# Copyright lowRISC contributors (OpenTitan project).
# Licensed under the Apache License, Version 2.0, see LICENSE for details.
# SPDX-License-Identifier: Apache-2.0
#
# This file was derived by lowRISC contributors (OpenTitan project) from the
# IHP Open PDK SRAM abstract RM_IHPSG13_1P_8192x32_c4.lef
# (https://github.com/IHP-GmbH/IHP-Open-PDK, ihp-sg13g2/libs.ref/sg13g2_sram/lef).
# It is a synthetic abstract, not an IHP release: the macro size and pins come
# from the Liberty view, the pin shapes, power straps and antenna values from
# the IHP abstract. IHP's original notice follows:
#
#   Copyright 2023 IHP PDK Authors
#
#   Licensed under the Apache License, Version 2.0 (the "License");
#   you may not use this file except in compliance with the License.
#   You may obtain a copy of the License at
#
#      https://www.apache.org/licenses/LICENSE-2.0
#
#   Unless required by applicable law or agreed to in writing, software
#   distributed under the License is distributed on an "AS IS" BASIS,
#   WITHOUT WARRANTIES OR CONDITIONS OF ANY KIND, either express or implied.
#   See the License for the specific language governing permissions and
#   limitations under the License.
#
#   Generated on Mon Apr  7 14:15:46 2025
#
# Generated by gen_synthetic_lef.py from the Liberty view. Do not edit.
# Synthetic abstract: no physical layout exists behind this macro.

VERSION 5.7 ;
BUSBITCHARS "[]" ;
DIVIDERCHAR "/" ;

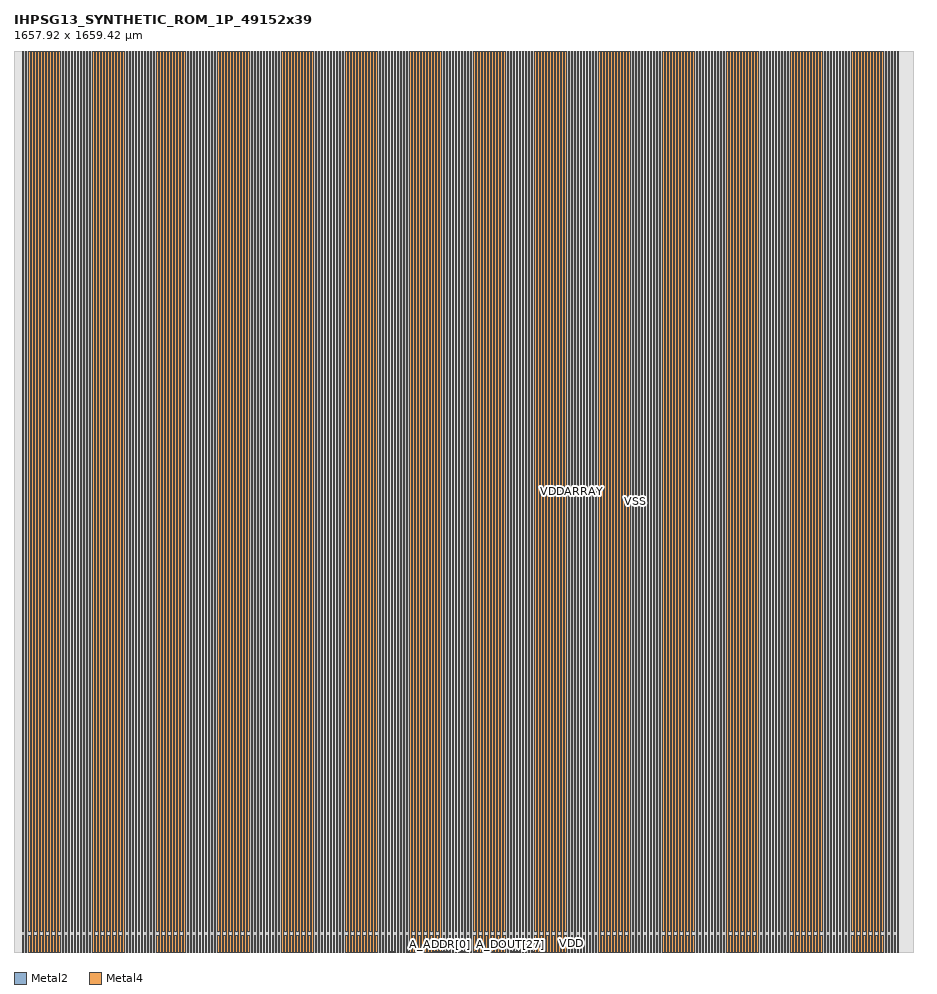
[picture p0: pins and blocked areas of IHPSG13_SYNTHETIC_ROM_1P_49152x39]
MACRO IHPSG13_SYNTHETIC_ROM_1P_49152x39
  CLASS BLOCK ;
  ORIGIN 0 0 ;
  FOREIGN IHPSG13_SYNTHETIC_ROM_1P_49152x39 0 0 ;
  SIZE 1657.92 BY 1659.42 ;
  SYMMETRY X Y R90 ;
  PIN A_DOUT[0]
    DIRECTION OUTPUT ;
    USE SIGNAL ;
    ANTENNADIFFAREA 0.988 LAYER Metal2 ;
    PORT
      LAYER Metal2 ;
        RECT 689.63 0 689.89 0.26 ;
    END
  END A_DOUT[0]
  PIN A_DOUT[1]
    DIRECTION OUTPUT ;
    USE SIGNAL ;
    ANTENNADIFFAREA 0.988 LAYER Metal2 ;
    PORT
      LAYER Metal2 ;
        RECT 694.43 0 694.69 0.26 ;
    END
  END A_DOUT[1]
  PIN A_DOUT[2]
    DIRECTION OUTPUT ;
    USE SIGNAL ;
    ANTENNADIFFAREA 0.988 LAYER Metal2 ;
    PORT
      LAYER Metal2 ;
        RECT 699.23 0 699.49 0.26 ;
    END
  END A_DOUT[2]
  PIN A_DOUT[3]
    DIRECTION OUTPUT ;
    USE SIGNAL ;
    ANTENNADIFFAREA 0.988 LAYER Metal2 ;
    PORT
      LAYER Metal2 ;
        RECT 704.03 0 704.29 0.26 ;
    END
  END A_DOUT[3]
  PIN A_DOUT[4]
    DIRECTION OUTPUT ;
    USE SIGNAL ;
    ANTENNADIFFAREA 0.988 LAYER Metal2 ;
    PORT
      LAYER Metal2 ;
        RECT 708.83 0 709.09 0.26 ;
    END
  END A_DOUT[4]
  PIN A_DOUT[5]
    DIRECTION OUTPUT ;
    USE SIGNAL ;
    ANTENNADIFFAREA 0.988 LAYER Metal2 ;
    PORT
      LAYER Metal2 ;
        RECT 713.63 0 713.89 0.26 ;
    END
  END A_DOUT[5]
  PIN A_DOUT[6]
    DIRECTION OUTPUT ;
    USE SIGNAL ;
    ANTENNADIFFAREA 0.988 LAYER Metal2 ;
    PORT
      LAYER Metal2 ;
        RECT 718.43 0 718.69 0.26 ;
    END
  END A_DOUT[6]
  PIN A_DOUT[7]
    DIRECTION OUTPUT ;
    USE SIGNAL ;
    ANTENNADIFFAREA 0.988 LAYER Metal2 ;
    PORT
      LAYER Metal2 ;
        RECT 723.23 0 723.49 0.26 ;
    END
  END A_DOUT[7]
  PIN A_DOUT[8]
    DIRECTION OUTPUT ;
    USE SIGNAL ;
    ANTENNADIFFAREA 0.988 LAYER Metal2 ;
    PORT
      LAYER Metal2 ;
        RECT 728.03 0 728.29 0.26 ;
    END
  END A_DOUT[8]
  PIN A_DOUT[9]
    DIRECTION OUTPUT ;
    USE SIGNAL ;
    ANTENNADIFFAREA 0.988 LAYER Metal2 ;
    PORT
      LAYER Metal2 ;
        RECT 732.83 0 733.09 0.26 ;
    END
  END A_DOUT[9]
  PIN A_DOUT[10]
    DIRECTION OUTPUT ;
    USE SIGNAL ;
    ANTENNADIFFAREA 0.988 LAYER Metal2 ;
    PORT
      LAYER Metal2 ;
        RECT 737.63 0 737.89 0.26 ;
    END
  END A_DOUT[10]
  PIN A_DOUT[11]
    DIRECTION OUTPUT ;
    USE SIGNAL ;
    ANTENNADIFFAREA 0.988 LAYER Metal2 ;
    PORT
      LAYER Metal2 ;
        RECT 742.43 0 742.69 0.26 ;
    END
  END A_DOUT[11]
  PIN A_DOUT[12]
    DIRECTION OUTPUT ;
    USE SIGNAL ;
    ANTENNADIFFAREA 0.988 LAYER Metal2 ;
    PORT
      LAYER Metal2 ;
        RECT 747.23 0 747.49 0.26 ;
    END
  END A_DOUT[12]
  PIN A_DOUT[13]
    DIRECTION OUTPUT ;
    USE SIGNAL ;
    ANTENNADIFFAREA 0.988 LAYER Metal2 ;
    PORT
      LAYER Metal2 ;
        RECT 752.03 0 752.29 0.26 ;
    END
  END A_DOUT[13]
  PIN A_DOUT[14]
    DIRECTION OUTPUT ;
    USE SIGNAL ;
    ANTENNADIFFAREA 0.988 LAYER Metal2 ;
    PORT
      LAYER Metal2 ;
        RECT 756.83 0 757.09 0.26 ;
    END
  END A_DOUT[14]
  PIN A_DOUT[15]
    DIRECTION OUTPUT ;
    USE SIGNAL ;
    ANTENNADIFFAREA 0.988 LAYER Metal2 ;
    PORT
      LAYER Metal2 ;
        RECT 761.63 0 761.89 0.26 ;
    END
  END A_DOUT[15]
  PIN A_DOUT[16]
    DIRECTION OUTPUT ;
    USE SIGNAL ;
    ANTENNADIFFAREA 0.988 LAYER Metal2 ;
    PORT
      LAYER Metal2 ;
        RECT 766.43 0 766.69 0.26 ;
    END
  END A_DOUT[16]
  PIN A_DOUT[17]
    DIRECTION OUTPUT ;
    USE SIGNAL ;
    ANTENNADIFFAREA 0.988 LAYER Metal2 ;
    PORT
      LAYER Metal2 ;
        RECT 771.23 0 771.49 0.26 ;
    END
  END A_DOUT[17]
  PIN A_DOUT[18]
    DIRECTION OUTPUT ;
    USE SIGNAL ;
    ANTENNADIFFAREA 0.988 LAYER Metal2 ;
    PORT
      LAYER Metal2 ;
        RECT 776.03 0 776.29 0.26 ;
    END
  END A_DOUT[18]
  PIN A_DLY
    DIRECTION INPUT ;
    USE SIGNAL ;
    ANTENNAMODEL OXIDE1 ;
      ANTENNAGATEAREA 0.20085 LAYER Metal2 ;
    PORT
      LAYER Metal2 ;
        RECT 780.83 0 781.09 0.26 ;
    END
  END A_DLY
  PIN A_ADDR[0]
    DIRECTION INPUT ;
    USE SIGNAL ;
    ANTENNAMODEL OXIDE1 ;
      ANTENNAGATEAREA 0.20085 LAYER Metal2 ;
    PORT
      LAYER Metal2 ;
        RECT 785.63 0 785.89 0.26 ;
    END
  END A_ADDR[0]
  PIN A_ADDR[1]
    DIRECTION INPUT ;
    USE SIGNAL ;
    ANTENNAMODEL OXIDE1 ;
      ANTENNAGATEAREA 0.20085 LAYER Metal2 ;
    PORT
      LAYER Metal2 ;
        RECT 790.43 0 790.69 0.26 ;
    END
  END A_ADDR[1]
  PIN A_ADDR[2]
    DIRECTION INPUT ;
    USE SIGNAL ;
    ANTENNAMODEL OXIDE1 ;
      ANTENNAGATEAREA 0.20085 LAYER Metal2 ;
    PORT
      LAYER Metal2 ;
        RECT 795.23 0 795.49 0.26 ;
    END
  END A_ADDR[2]
  PIN A_ADDR[3]
    DIRECTION INPUT ;
    USE SIGNAL ;
    ANTENNAMODEL OXIDE1 ;
      ANTENNAGATEAREA 0.20085 LAYER Metal2 ;
    PORT
      LAYER Metal2 ;
        RECT 800.03 0 800.29 0.26 ;
    END
  END A_ADDR[3]
  PIN A_ADDR[4]
    DIRECTION INPUT ;
    USE SIGNAL ;
    ANTENNAMODEL OXIDE1 ;
      ANTENNAGATEAREA 0.20085 LAYER Metal2 ;
    PORT
      LAYER Metal2 ;
        RECT 804.83 0 805.09 0.26 ;
    END
  END A_ADDR[4]
  PIN A_ADDR[5]
    DIRECTION INPUT ;
    USE SIGNAL ;
    ANTENNAMODEL OXIDE1 ;
      ANTENNAGATEAREA 0.20085 LAYER Metal2 ;
    PORT
      LAYER Metal2 ;
        RECT 809.63 0 809.89 0.26 ;
    END
  END A_ADDR[5]
  PIN A_ADDR[6]
    DIRECTION INPUT ;
    USE SIGNAL ;
    ANTENNAMODEL OXIDE1 ;
      ANTENNAGATEAREA 0.20085 LAYER Metal2 ;
    PORT
      LAYER Metal2 ;
        RECT 814.43 0 814.69 0.26 ;
    END
  END A_ADDR[6]
  PIN A_ADDR[7]
    DIRECTION INPUT ;
    USE SIGNAL ;
    ANTENNAMODEL OXIDE1 ;
      ANTENNAGATEAREA 0.20085 LAYER Metal2 ;
    PORT
      LAYER Metal2 ;
        RECT 819.23 0 819.49 0.26 ;
    END
  END A_ADDR[7]
  PIN A_ADDR[8]
    DIRECTION INPUT ;
    USE SIGNAL ;
    ANTENNAMODEL OXIDE1 ;
      ANTENNAGATEAREA 0.20085 LAYER Metal2 ;
    PORT
      LAYER Metal2 ;
        RECT 824.03 0 824.29 0.26 ;
    END
  END A_ADDR[8]
  PIN A_ADDR[9]
    DIRECTION INPUT ;
    USE SIGNAL ;
    ANTENNAMODEL OXIDE1 ;
      ANTENNAGATEAREA 0.20085 LAYER Metal2 ;
    PORT
      LAYER Metal2 ;
        RECT 828.83 0 829.09 0.26 ;
    END
  END A_ADDR[9]
  PIN A_ADDR[10]
    DIRECTION INPUT ;
    USE SIGNAL ;
    ANTENNAMODEL OXIDE1 ;
      ANTENNAGATEAREA 0.20085 LAYER Metal2 ;
    PORT
      LAYER Metal2 ;
        RECT 833.63 0 833.89 0.26 ;
    END
  END A_ADDR[10]
  PIN A_ADDR[11]
    DIRECTION INPUT ;
    USE SIGNAL ;
    ANTENNAMODEL OXIDE1 ;
      ANTENNAGATEAREA 0.20085 LAYER Metal2 ;
    PORT
      LAYER Metal2 ;
        RECT 838.43 0 838.69 0.26 ;
    END
  END A_ADDR[11]
  PIN A_ADDR[12]
    DIRECTION INPUT ;
    USE SIGNAL ;
    ANTENNAMODEL OXIDE1 ;
      ANTENNAGATEAREA 0.20085 LAYER Metal2 ;
    PORT
      LAYER Metal2 ;
        RECT 843.23 0 843.49 0.26 ;
    END
  END A_ADDR[12]
  PIN A_ADDR[13]
    DIRECTION INPUT ;
    USE SIGNAL ;
    ANTENNAMODEL OXIDE1 ;
      ANTENNAGATEAREA 0.20085 LAYER Metal2 ;
    PORT
      LAYER Metal2 ;
        RECT 848.03 0 848.29 0.26 ;
    END
  END A_ADDR[13]
  PIN A_ADDR[14]
    DIRECTION INPUT ;
    USE SIGNAL ;
    ANTENNAMODEL OXIDE1 ;
      ANTENNAGATEAREA 0.20085 LAYER Metal2 ;
    PORT
      LAYER Metal2 ;
        RECT 852.83 0 853.09 0.26 ;
    END
  END A_ADDR[14]
  PIN A_ADDR[15]
    DIRECTION INPUT ;
    USE SIGNAL ;
    ANTENNAMODEL OXIDE1 ;
      ANTENNAGATEAREA 0.20085 LAYER Metal2 ;
    PORT
      LAYER Metal2 ;
        RECT 857.63 0 857.89 0.26 ;
    END
  END A_ADDR[15]
  PIN A_REN
    DIRECTION INPUT ;
    USE SIGNAL ;
    ANTENNAMODEL OXIDE1 ;
      ANTENNAGATEAREA 0.20085 LAYER Metal2 ;
    PORT
      LAYER Metal2 ;
        RECT 862.43 0 862.69 0.26 ;
    END
  END A_REN
  PIN A_MEN
    DIRECTION INPUT ;
    USE SIGNAL ;
    ANTENNAMODEL OXIDE1 ;
      ANTENNAGATEAREA 0.20085 LAYER Metal2 ;
    PORT
      LAYER Metal2 ;
        RECT 867.23 0 867.49 0.26 ;
    END
  END A_MEN
  PIN A_CLK
    DIRECTION INPUT ;
    USE SIGNAL ;
    ANTENNAMODEL OXIDE1 ;
      ANTENNAGATEAREA 0.20085 LAYER Metal2 ;
    PORT
      LAYER Metal2 ;
        RECT 872.03 0 872.29 0.26 ;
    END
  END A_CLK
  PIN A_DOUT[19]
    DIRECTION OUTPUT ;
    USE SIGNAL ;
    ANTENNADIFFAREA 0.988 LAYER Metal2 ;
    PORT
      LAYER Metal2 ;
        RECT 876.83 0 877.09 0.26 ;
    END
  END A_DOUT[19]
  PIN A_DOUT[20]
    DIRECTION OUTPUT ;
    USE SIGNAL ;
    ANTENNADIFFAREA 0.988 LAYER Metal2 ;
    PORT
      LAYER Metal2 ;
        RECT 881.63 0 881.89 0.26 ;
    END
  END A_DOUT[20]
  PIN A_DOUT[21]
    DIRECTION OUTPUT ;
    USE SIGNAL ;
    ANTENNADIFFAREA 0.988 LAYER Metal2 ;
    PORT
      LAYER Metal2 ;
        RECT 886.43 0 886.69 0.26 ;
    END
  END A_DOUT[21]
  PIN A_DOUT[22]
    DIRECTION OUTPUT ;
    USE SIGNAL ;
    ANTENNADIFFAREA 0.988 LAYER Metal2 ;
    PORT
      LAYER Metal2 ;
        RECT 891.23 0 891.49 0.26 ;
    END
  END A_DOUT[22]
  PIN A_DOUT[23]
    DIRECTION OUTPUT ;
    USE SIGNAL ;
    ANTENNADIFFAREA 0.988 LAYER Metal2 ;
    PORT
      LAYER Metal2 ;
        RECT 896.03 0 896.29 0.26 ;
    END
  END A_DOUT[23]
  PIN A_DOUT[24]
    DIRECTION OUTPUT ;
    USE SIGNAL ;
    ANTENNADIFFAREA 0.988 LAYER Metal2 ;
    PORT
      LAYER Metal2 ;
        RECT 900.83 0 901.09 0.26 ;
    END
  END A_DOUT[24]
  PIN A_DOUT[25]
    DIRECTION OUTPUT ;
    USE SIGNAL ;
    ANTENNADIFFAREA 0.988 LAYER Metal2 ;
    PORT
      LAYER Metal2 ;
        RECT 905.63 0 905.89 0.26 ;
    END
  END A_DOUT[25]
  PIN A_DOUT[26]
    DIRECTION OUTPUT ;
    USE SIGNAL ;
    ANTENNADIFFAREA 0.988 LAYER Metal2 ;
    PORT
      LAYER Metal2 ;
        RECT 910.43 0 910.69 0.26 ;
    END
  END A_DOUT[26]
  PIN A_DOUT[27]
    DIRECTION OUTPUT ;
    USE SIGNAL ;
    ANTENNADIFFAREA 0.988 LAYER Metal2 ;
    PORT
      LAYER Metal2 ;
        RECT 915.23 0 915.49 0.26 ;
    END
  END A_DOUT[27]
  PIN A_DOUT[28]
    DIRECTION OUTPUT ;
    USE SIGNAL ;
    ANTENNADIFFAREA 0.988 LAYER Metal2 ;
    PORT
      LAYER Metal2 ;
        RECT 920.03 0 920.29 0.26 ;
    END
  END A_DOUT[28]
  PIN A_DOUT[29]
    DIRECTION OUTPUT ;
    USE SIGNAL ;
    ANTENNADIFFAREA 0.988 LAYER Metal2 ;
    PORT
      LAYER Metal2 ;
        RECT 924.83 0 925.09 0.26 ;
    END
  END A_DOUT[29]
  PIN A_DOUT[30]
    DIRECTION OUTPUT ;
    USE SIGNAL ;
    ANTENNADIFFAREA 0.988 LAYER Metal2 ;
    PORT
      LAYER Metal2 ;
        RECT 929.63 0 929.89 0.26 ;
    END
  END A_DOUT[30]
  PIN A_DOUT[31]
    DIRECTION OUTPUT ;
    USE SIGNAL ;
    ANTENNADIFFAREA 0.988 LAYER Metal2 ;
    PORT
      LAYER Metal2 ;
        RECT 934.43 0 934.69 0.26 ;
    END
  END A_DOUT[31]
  PIN A_DOUT[32]
    DIRECTION OUTPUT ;
    USE SIGNAL ;
    ANTENNADIFFAREA 0.988 LAYER Metal2 ;
    PORT
      LAYER Metal2 ;
        RECT 939.23 0 939.49 0.26 ;
    END
  END A_DOUT[32]
  PIN A_DOUT[33]
    DIRECTION OUTPUT ;
    USE SIGNAL ;
    ANTENNADIFFAREA 0.988 LAYER Metal2 ;
    PORT
      LAYER Metal2 ;
        RECT 944.03 0 944.29 0.26 ;
    END
  END A_DOUT[33]
  PIN A_DOUT[34]
    DIRECTION OUTPUT ;
    USE SIGNAL ;
    ANTENNADIFFAREA 0.988 LAYER Metal2 ;
    PORT
      LAYER Metal2 ;
        RECT 948.83 0 949.09 0.26 ;
    END
  END A_DOUT[34]
  PIN A_DOUT[35]
    DIRECTION OUTPUT ;
    USE SIGNAL ;
    ANTENNADIFFAREA 0.988 LAYER Metal2 ;
    PORT
      LAYER Metal2 ;
        RECT 953.63 0 953.89 0.26 ;
    END
  END A_DOUT[35]
  PIN A_DOUT[36]
    DIRECTION OUTPUT ;
    USE SIGNAL ;
    ANTENNADIFFAREA 0.988 LAYER Metal2 ;
    PORT
      LAYER Metal2 ;
        RECT 958.43 0 958.69 0.26 ;
    END
  END A_DOUT[36]
  PIN A_DOUT[37]
    DIRECTION OUTPUT ;
    USE SIGNAL ;
    ANTENNADIFFAREA 0.988 LAYER Metal2 ;
    PORT
      LAYER Metal2 ;
        RECT 963.23 0 963.49 0.26 ;
    END
  END A_DOUT[37]
  PIN A_DOUT[38]
    DIRECTION OUTPUT ;
    USE SIGNAL ;
    ANTENNADIFFAREA 0.988 LAYER Metal2 ;
    PORT
      LAYER Metal2 ;
        RECT 968.03 0 968.29 0.26 ;
    END
  END A_DOUT[38]
  PIN VDD
    DIRECTION INOUT ;
    USE POWER ;
    PORT
      LAYER Metal4 ;
        RECT 15.5 0 18.31 30.425 ;
    END
    PORT
      LAYER Metal4 ;
        RECT 26.74 0 29.55 30.425 ;
    END
    PORT
      LAYER Metal4 ;
        RECT 37.98 0 40.79 30.425 ;
    END
    PORT
      LAYER Metal4 ;
        RECT 49.22 0 52.03 30.425 ;
    END
    PORT
      LAYER Metal4 ;
        RECT 60.46 0 63.27 30.425 ;
    END
    PORT
      LAYER Metal4 ;
        RECT 71.7 0 74.51 30.425 ;
    END
    PORT
      LAYER Metal4 ;
        RECT 82.94 0 85.75 30.425 ;
    END
    PORT
      LAYER Metal4 ;
        RECT 94.18 0 96.99 30.425 ;
    END
    PORT
      LAYER Metal4 ;
        RECT 105.42 0 108.23 30.425 ;
    END
    PORT
      LAYER Metal4 ;
        RECT 116.66 0 119.47 30.425 ;
    END
    PORT
      LAYER Metal4 ;
        RECT 127.9 0 130.71 30.425 ;
    END
    PORT
      LAYER Metal4 ;
        RECT 139.14 0 141.95 30.425 ;
    END
    PORT
      LAYER Metal4 ;
        RECT 150.38 0 153.19 30.425 ;
    END
    PORT
      LAYER Metal4 ;
        RECT 161.62 0 164.43 30.425 ;
    END
    PORT
      LAYER Metal4 ;
        RECT 172.86 0 175.67 30.425 ;
    END
    PORT
      LAYER Metal4 ;
        RECT 184.1 0 186.91 30.425 ;
    END
    PORT
      LAYER Metal4 ;
        RECT 195.34 0 198.15 30.425 ;
    END
    PORT
      LAYER Metal4 ;
        RECT 206.58 0 209.39 30.425 ;
    END
    PORT
      LAYER Metal4 ;
        RECT 217.82 0 220.63 30.425 ;
    END
    PORT
      LAYER Metal4 ;
        RECT 229.06 0 231.87 30.425 ;
    END
    PORT
      LAYER Metal4 ;
        RECT 240.3 0 243.11 30.425 ;
    END
    PORT
      LAYER Metal4 ;
        RECT 251.54 0 254.35 30.425 ;
    END
    PORT
      LAYER Metal4 ;
        RECT 262.78 0 265.59 30.425 ;
    END
    PORT
      LAYER Metal4 ;
        RECT 274.02 0 276.83 30.425 ;
    END
    PORT
      LAYER Metal4 ;
        RECT 285.26 0 288.07 30.425 ;
    END
    PORT
      LAYER Metal4 ;
        RECT 296.5 0 299.31 30.425 ;
    END
    PORT
      LAYER Metal4 ;
        RECT 307.74 0 310.55 30.425 ;
    END
    PORT
      LAYER Metal4 ;
        RECT 318.98 0 321.79 30.425 ;
    END
    PORT
      LAYER Metal4 ;
        RECT 330.22 0 333.03 30.425 ;
    END
    PORT
      LAYER Metal4 ;
        RECT 341.46 0 344.27 30.425 ;
    END
    PORT
      LAYER Metal4 ;
        RECT 352.7 0 355.51 30.425 ;
    END
    PORT
      LAYER Metal4 ;
        RECT 363.94 0 366.75 30.425 ;
    END
    PORT
      LAYER Metal4 ;
        RECT 375.18 0 377.99 30.425 ;
    END
    PORT
      LAYER Metal4 ;
        RECT 386.42 0 389.23 30.425 ;
    END
    PORT
      LAYER Metal4 ;
        RECT 397.66 0 400.47 30.425 ;
    END
    PORT
      LAYER Metal4 ;
        RECT 408.9 0 411.71 30.425 ;
    END
    PORT
      LAYER Metal4 ;
        RECT 420.14 0 422.95 30.425 ;
    END
    PORT
      LAYER Metal4 ;
        RECT 431.38 0 434.19 30.425 ;
    END
    PORT
      LAYER Metal4 ;
        RECT 442.62 0 445.43 30.425 ;
    END
    PORT
      LAYER Metal4 ;
        RECT 453.86 0 456.67 30.425 ;
    END
    PORT
      LAYER Metal4 ;
        RECT 465.1 0 467.91 30.425 ;
    END
    PORT
      LAYER Metal4 ;
        RECT 476.34 0 479.15 30.425 ;
    END
    PORT
      LAYER Metal4 ;
        RECT 487.58 0 490.39 30.425 ;
    END
    PORT
      LAYER Metal4 ;
        RECT 498.82 0 501.63 30.425 ;
    END
    PORT
      LAYER Metal4 ;
        RECT 510.06 0 512.87 30.425 ;
    END
    PORT
      LAYER Metal4 ;
        RECT 521.3 0 524.11 30.425 ;
    END
    PORT
      LAYER Metal4 ;
        RECT 532.54 0 535.35 30.425 ;
    END
    PORT
      LAYER Metal4 ;
        RECT 543.78 0 546.59 30.425 ;
    END
    PORT
      LAYER Metal4 ;
        RECT 555.02 0 557.83 30.425 ;
    END
    PORT
      LAYER Metal4 ;
        RECT 566.26 0 569.07 30.425 ;
    END
    PORT
      LAYER Metal4 ;
        RECT 577.5 0 580.31 30.425 ;
    END
    PORT
      LAYER Metal4 ;
        RECT 588.74 0 591.55 30.425 ;
    END
    PORT
      LAYER Metal4 ;
        RECT 599.98 0 602.79 30.425 ;
    END
    PORT
      LAYER Metal4 ;
        RECT 611.22 0 614.03 30.425 ;
    END
    PORT
      LAYER Metal4 ;
        RECT 622.46 0 625.27 30.425 ;
    END
    PORT
      LAYER Metal4 ;
        RECT 633.7 0 636.51 30.425 ;
    END
    PORT
      LAYER Metal4 ;
        RECT 644.94 0 647.75 30.425 ;
    END
    PORT
      LAYER Metal4 ;
        RECT 656.18 0 658.99 30.425 ;
    END
    PORT
      LAYER Metal4 ;
        RECT 667.42 0 670.23 30.425 ;
    END
    PORT
      LAYER Metal4 ;
        RECT 678.66 0 681.47 30.425 ;
    END
    PORT
      LAYER Metal4 ;
        RECT 689.9 0 692.71 30.425 ;
    END
    PORT
      LAYER Metal4 ;
        RECT 701.14 0 703.95 30.425 ;
    END
    PORT
      LAYER Metal4 ;
        RECT 712.38 0 715.19 30.425 ;
    END
    PORT
      LAYER Metal4 ;
        RECT 723.62 0 726.43 30.425 ;
    END
    PORT
      LAYER Metal4 ;
        RECT 734.86 0 737.67 30.425 ;
    END
    PORT
      LAYER Metal4 ;
        RECT 746.1 0 748.91 30.425 ;
    END
    PORT
      LAYER Metal4 ;
        RECT 757.34 0 760.15 30.425 ;
    END
    PORT
      LAYER Metal4 ;
        RECT 768.58 0 771.39 30.425 ;
    END
    PORT
      LAYER Metal4 ;
        RECT 779.82 0 782.63 30.425 ;
    END
    PORT
      LAYER Metal4 ;
        RECT 791.06 0 793.87 30.425 ;
    END
    PORT
      LAYER Metal4 ;
        RECT 802.3 0 805.11 30.425 ;
    END
    PORT
      LAYER Metal4 ;
        RECT 813.54 0 816.35 30.425 ;
    END
    PORT
      LAYER Metal4 ;
        RECT 824.78 0 827.59 30.425 ;
    END
    PORT
      LAYER Metal4 ;
        RECT 836.02 0 838.83 30.425 ;
    END
    PORT
      LAYER Metal4 ;
        RECT 847.26 0 850.07 30.425 ;
    END
    PORT
      LAYER Metal4 ;
        RECT 858.5 0 861.31 30.425 ;
    END
    PORT
      LAYER Metal4 ;
        RECT 869.74 0 872.55 30.425 ;
    END
    PORT
      LAYER Metal4 ;
        RECT 880.98 0 883.79 30.425 ;
    END
    PORT
      LAYER Metal4 ;
        RECT 892.22 0 895.03 30.425 ;
    END
    PORT
      LAYER Metal4 ;
        RECT 903.46 0 906.27 30.425 ;
    END
    PORT
      LAYER Metal4 ;
        RECT 914.7 0 917.51 30.425 ;
    END
    PORT
      LAYER Metal4 ;
        RECT 925.94 0 928.75 30.425 ;
    END
    PORT
      LAYER Metal4 ;
        RECT 937.18 0 939.99 30.425 ;
    END
    PORT
      LAYER Metal4 ;
        RECT 948.42 0 951.23 30.425 ;
    END
    PORT
      LAYER Metal4 ;
        RECT 959.66 0 962.47 30.425 ;
    END
    PORT
      LAYER Metal4 ;
        RECT 970.9 0 973.71 30.425 ;
    END
    PORT
      LAYER Metal4 ;
        RECT 982.14 0 984.95 30.425 ;
    END
    PORT
      LAYER Metal4 ;
        RECT 993.38 0 996.19 30.425 ;
    END
    PORT
      LAYER Metal4 ;
        RECT 1004.62 0 1007.43 30.425 ;
    END
    PORT
      LAYER Metal4 ;
        RECT 1015.86 0 1018.67 30.425 ;
    END
    PORT
      LAYER Metal4 ;
        RECT 1027.1 0 1029.91 30.425 ;
    END
    PORT
      LAYER Metal4 ;
        RECT 1038.34 0 1041.15 30.425 ;
    END
    PORT
      LAYER Metal4 ;
        RECT 1049.58 0 1052.39 30.425 ;
    END
    PORT
      LAYER Metal4 ;
        RECT 1060.82 0 1063.63 30.425 ;
    END
    PORT
      LAYER Metal4 ;
        RECT 1072.06 0 1074.87 30.425 ;
    END
    PORT
      LAYER Metal4 ;
        RECT 1083.3 0 1086.11 30.425 ;
    END
    PORT
      LAYER Metal4 ;
        RECT 1094.54 0 1097.35 30.425 ;
    END
    PORT
      LAYER Metal4 ;
        RECT 1105.78 0 1108.59 30.425 ;
    END
    PORT
      LAYER Metal4 ;
        RECT 1117.02 0 1119.83 30.425 ;
    END
    PORT
      LAYER Metal4 ;
        RECT 1128.26 0 1131.07 30.425 ;
    END
    PORT
      LAYER Metal4 ;
        RECT 1139.5 0 1142.31 30.425 ;
    END
    PORT
      LAYER Metal4 ;
        RECT 1150.74 0 1153.55 30.425 ;
    END
    PORT
      LAYER Metal4 ;
        RECT 1161.98 0 1164.79 30.425 ;
    END
    PORT
      LAYER Metal4 ;
        RECT 1173.22 0 1176.03 30.425 ;
    END
    PORT
      LAYER Metal4 ;
        RECT 1184.46 0 1187.27 30.425 ;
    END
    PORT
      LAYER Metal4 ;
        RECT 1195.7 0 1198.51 30.425 ;
    END
    PORT
      LAYER Metal4 ;
        RECT 1206.94 0 1209.75 30.425 ;
    END
    PORT
      LAYER Metal4 ;
        RECT 1218.18 0 1220.99 30.425 ;
    END
    PORT
      LAYER Metal4 ;
        RECT 1229.42 0 1232.23 30.425 ;
    END
    PORT
      LAYER Metal4 ;
        RECT 1240.66 0 1243.47 30.425 ;
    END
    PORT
      LAYER Metal4 ;
        RECT 1251.9 0 1254.71 30.425 ;
    END
    PORT
      LAYER Metal4 ;
        RECT 1263.14 0 1265.95 30.425 ;
    END
    PORT
      LAYER Metal4 ;
        RECT 1274.38 0 1277.19 30.425 ;
    END
    PORT
      LAYER Metal4 ;
        RECT 1285.62 0 1288.43 30.425 ;
    END
    PORT
      LAYER Metal4 ;
        RECT 1296.86 0 1299.67 30.425 ;
    END
    PORT
      LAYER Metal4 ;
        RECT 1308.1 0 1310.91 30.425 ;
    END
    PORT
      LAYER Metal4 ;
        RECT 1319.34 0 1322.15 30.425 ;
    END
    PORT
      LAYER Metal4 ;
        RECT 1330.58 0 1333.39 30.425 ;
    END
    PORT
      LAYER Metal4 ;
        RECT 1341.82 0 1344.63 30.425 ;
    END
    PORT
      LAYER Metal4 ;
        RECT 1353.06 0 1355.87 30.425 ;
    END
    PORT
      LAYER Metal4 ;
        RECT 1364.3 0 1367.11 30.425 ;
    END
    PORT
      LAYER Metal4 ;
        RECT 1375.54 0 1378.35 30.425 ;
    END
    PORT
      LAYER Metal4 ;
        RECT 1386.78 0 1389.59 30.425 ;
    END
    PORT
      LAYER Metal4 ;
        RECT 1398.02 0 1400.83 30.425 ;
    END
    PORT
      LAYER Metal4 ;
        RECT 1409.26 0 1412.07 30.425 ;
    END
    PORT
      LAYER Metal4 ;
        RECT 1420.5 0 1423.31 30.425 ;
    END
    PORT
      LAYER Metal4 ;
        RECT 1431.74 0 1434.55 30.425 ;
    END
    PORT
      LAYER Metal4 ;
        RECT 1442.98 0 1445.79 30.425 ;
    END
    PORT
      LAYER Metal4 ;
        RECT 1454.22 0 1457.03 30.425 ;
    END
    PORT
      LAYER Metal4 ;
        RECT 1465.46 0 1468.27 30.425 ;
    END
    PORT
      LAYER Metal4 ;
        RECT 1476.7 0 1479.51 30.425 ;
    END
    PORT
      LAYER Metal4 ;
        RECT 1487.94 0 1490.75 30.425 ;
    END
    PORT
      LAYER Metal4 ;
        RECT 1499.18 0 1501.99 30.425 ;
    END
    PORT
      LAYER Metal4 ;
        RECT 1510.42 0 1513.23 30.425 ;
    END
    PORT
      LAYER Metal4 ;
        RECT 1521.66 0 1524.47 30.425 ;
    END
    PORT
      LAYER Metal4 ;
        RECT 1532.9 0 1535.71 30.425 ;
    END
    PORT
      LAYER Metal4 ;
        RECT 1544.14 0 1546.95 30.425 ;
    END
    PORT
      LAYER Metal4 ;
        RECT 1555.38 0 1558.19 30.425 ;
    END
    PORT
      LAYER Metal4 ;
        RECT 1566.62 0 1569.43 30.425 ;
    END
    PORT
      LAYER Metal4 ;
        RECT 1577.86 0 1580.67 30.425 ;
    END
    PORT
      LAYER Metal4 ;
        RECT 1589.1 0 1591.91 30.425 ;
    END
    PORT
      LAYER Metal4 ;
        RECT 1600.34 0 1603.15 30.425 ;
    END
    PORT
      LAYER Metal4 ;
        RECT 1611.58 0 1614.39 30.425 ;
    END
    PORT
      LAYER Metal4 ;
        RECT 1622.82 0 1625.63 30.425 ;
    END
  END VDD
  PIN VDDARRAY
    DIRECTION INOUT ;
    USE POWER ;
    PORT
      LAYER Metal4 ;
        RECT 15.5 37.065 18.31 1659.42 ;
    END
    PORT
      LAYER Metal4 ;
        RECT 26.74 37.065 29.55 1659.42 ;
    END
    PORT
      LAYER Metal4 ;
        RECT 37.98 37.065 40.79 1659.42 ;
    END
    PORT
      LAYER Metal4 ;
        RECT 49.22 37.065 52.03 1659.42 ;
    END
    PORT
      LAYER Metal4 ;
        RECT 60.46 37.065 63.27 1659.42 ;
    END
    PORT
      LAYER Metal4 ;
        RECT 71.7 37.065 74.51 1659.42 ;
    END
    PORT
      LAYER Metal4 ;
        RECT 82.94 37.065 85.75 1659.42 ;
    END
    PORT
      LAYER Metal4 ;
        RECT 94.18 37.065 96.99 1659.42 ;
    END
    PORT
      LAYER Metal4 ;
        RECT 105.42 37.065 108.23 1659.42 ;
    END
    PORT
      LAYER Metal4 ;
        RECT 116.66 37.065 119.47 1659.42 ;
    END
    PORT
      LAYER Metal4 ;
        RECT 127.9 37.065 130.71 1659.42 ;
    END
    PORT
      LAYER Metal4 ;
        RECT 139.14 37.065 141.95 1659.42 ;
    END
    PORT
      LAYER Metal4 ;
        RECT 150.38 37.065 153.19 1659.42 ;
    END
    PORT
      LAYER Metal4 ;
        RECT 161.62 37.065 164.43 1659.42 ;
    END
    PORT
      LAYER Metal4 ;
        RECT 172.86 37.065 175.67 1659.42 ;
    END
    PORT
      LAYER Metal4 ;
        RECT 184.1 37.065 186.91 1659.42 ;
    END
    PORT
      LAYER Metal4 ;
        RECT 195.34 37.065 198.15 1659.42 ;
    END
    PORT
      LAYER Metal4 ;
        RECT 206.58 37.065 209.39 1659.42 ;
    END
    PORT
      LAYER Metal4 ;
        RECT 217.82 37.065 220.63 1659.42 ;
    END
    PORT
      LAYER Metal4 ;
        RECT 229.06 37.065 231.87 1659.42 ;
    END
    PORT
      LAYER Metal4 ;
        RECT 240.3 37.065 243.11 1659.42 ;
    END
    PORT
      LAYER Metal4 ;
        RECT 251.54 37.065 254.35 1659.42 ;
    END
    PORT
      LAYER Metal4 ;
        RECT 262.78 37.065 265.59 1659.42 ;
    END
    PORT
      LAYER Metal4 ;
        RECT 274.02 37.065 276.83 1659.42 ;
    END
    PORT
      LAYER Metal4 ;
        RECT 285.26 37.065 288.07 1659.42 ;
    END
    PORT
      LAYER Metal4 ;
        RECT 296.5 37.065 299.31 1659.42 ;
    END
    PORT
      LAYER Metal4 ;
        RECT 307.74 37.065 310.55 1659.42 ;
    END
    PORT
      LAYER Metal4 ;
        RECT 318.98 37.065 321.79 1659.42 ;
    END
    PORT
      LAYER Metal4 ;
        RECT 330.22 37.065 333.03 1659.42 ;
    END
    PORT
      LAYER Metal4 ;
        RECT 341.46 37.065 344.27 1659.42 ;
    END
    PORT
      LAYER Metal4 ;
        RECT 352.7 37.065 355.51 1659.42 ;
    END
    PORT
      LAYER Metal4 ;
        RECT 363.94 37.065 366.75 1659.42 ;
    END
    PORT
      LAYER Metal4 ;
        RECT 375.18 37.065 377.99 1659.42 ;
    END
    PORT
      LAYER Metal4 ;
        RECT 386.42 37.065 389.23 1659.42 ;
    END
    PORT
      LAYER Metal4 ;
        RECT 397.66 37.065 400.47 1659.42 ;
    END
    PORT
      LAYER Metal4 ;
        RECT 408.9 37.065 411.71 1659.42 ;
    END
    PORT
      LAYER Metal4 ;
        RECT 420.14 37.065 422.95 1659.42 ;
    END
    PORT
      LAYER Metal4 ;
        RECT 431.38 37.065 434.19 1659.42 ;
    END
    PORT
      LAYER Metal4 ;
        RECT 442.62 37.065 445.43 1659.42 ;
    END
    PORT
      LAYER Metal4 ;
        RECT 453.86 37.065 456.67 1659.42 ;
    END
    PORT
      LAYER Metal4 ;
        RECT 465.1 37.065 467.91 1659.42 ;
    END
    PORT
      LAYER Metal4 ;
        RECT 476.34 37.065 479.15 1659.42 ;
    END
    PORT
      LAYER Metal4 ;
        RECT 487.58 37.065 490.39 1659.42 ;
    END
    PORT
      LAYER Metal4 ;
        RECT 498.82 37.065 501.63 1659.42 ;
    END
    PORT
      LAYER Metal4 ;
        RECT 510.06 37.065 512.87 1659.42 ;
    END
    PORT
      LAYER Metal4 ;
        RECT 521.3 37.065 524.11 1659.42 ;
    END
    PORT
      LAYER Metal4 ;
        RECT 532.54 37.065 535.35 1659.42 ;
    END
    PORT
      LAYER Metal4 ;
        RECT 543.78 37.065 546.59 1659.42 ;
    END
    PORT
      LAYER Metal4 ;
        RECT 555.02 37.065 557.83 1659.42 ;
    END
    PORT
      LAYER Metal4 ;
        RECT 566.26 37.065 569.07 1659.42 ;
    END
    PORT
      LAYER Metal4 ;
        RECT 577.5 37.065 580.31 1659.42 ;
    END
    PORT
      LAYER Metal4 ;
        RECT 588.74 37.065 591.55 1659.42 ;
    END
    PORT
      LAYER Metal4 ;
        RECT 599.98 37.065 602.79 1659.42 ;
    END
    PORT
      LAYER Metal4 ;
        RECT 611.22 37.065 614.03 1659.42 ;
    END
    PORT
      LAYER Metal4 ;
        RECT 622.46 37.065 625.27 1659.42 ;
    END
    PORT
      LAYER Metal4 ;
        RECT 633.7 37.065 636.51 1659.42 ;
    END
    PORT
      LAYER Metal4 ;
        RECT 644.94 37.065 647.75 1659.42 ;
    END
    PORT
      LAYER Metal4 ;
        RECT 656.18 37.065 658.99 1659.42 ;
    END
    PORT
      LAYER Metal4 ;
        RECT 667.42 37.065 670.23 1659.42 ;
    END
    PORT
      LAYER Metal4 ;
        RECT 678.66 37.065 681.47 1659.42 ;
    END
    PORT
      LAYER Metal4 ;
        RECT 689.9 37.065 692.71 1659.42 ;
    END
    PORT
      LAYER Metal4 ;
        RECT 701.14 37.065 703.95 1659.42 ;
    END
    PORT
      LAYER Metal4 ;
        RECT 712.38 37.065 715.19 1659.42 ;
    END
    PORT
      LAYER Metal4 ;
        RECT 723.62 37.065 726.43 1659.42 ;
    END
    PORT
      LAYER Metal4 ;
        RECT 734.86 37.065 737.67 1659.42 ;
    END
    PORT
      LAYER Metal4 ;
        RECT 746.1 37.065 748.91 1659.42 ;
    END
    PORT
      LAYER Metal4 ;
        RECT 757.34 37.065 760.15 1659.42 ;
    END
    PORT
      LAYER Metal4 ;
        RECT 768.58 37.065 771.39 1659.42 ;
    END
    PORT
      LAYER Metal4 ;
        RECT 779.82 37.065 782.63 1659.42 ;
    END
    PORT
      LAYER Metal4 ;
        RECT 791.06 37.065 793.87 1659.42 ;
    END
    PORT
      LAYER Metal4 ;
        RECT 802.3 37.065 805.11 1659.42 ;
    END
    PORT
      LAYER Metal4 ;
        RECT 813.54 37.065 816.35 1659.42 ;
    END
    PORT
      LAYER Metal4 ;
        RECT 824.78 37.065 827.59 1659.42 ;
    END
    PORT
      LAYER Metal4 ;
        RECT 836.02 37.065 838.83 1659.42 ;
    END
    PORT
      LAYER Metal4 ;
        RECT 847.26 37.065 850.07 1659.42 ;
    END
    PORT
      LAYER Metal4 ;
        RECT 858.5 37.065 861.31 1659.42 ;
    END
    PORT
      LAYER Metal4 ;
        RECT 869.74 37.065 872.55 1659.42 ;
    END
    PORT
      LAYER Metal4 ;
        RECT 880.98 37.065 883.79 1659.42 ;
    END
    PORT
      LAYER Metal4 ;
        RECT 892.22 37.065 895.03 1659.42 ;
    END
    PORT
      LAYER Metal4 ;
        RECT 903.46 37.065 906.27 1659.42 ;
    END
    PORT
      LAYER Metal4 ;
        RECT 914.7 37.065 917.51 1659.42 ;
    END
    PORT
      LAYER Metal4 ;
        RECT 925.94 37.065 928.75 1659.42 ;
    END
    PORT
      LAYER Metal4 ;
        RECT 937.18 37.065 939.99 1659.42 ;
    END
    PORT
      LAYER Metal4 ;
        RECT 948.42 37.065 951.23 1659.42 ;
    END
    PORT
      LAYER Metal4 ;
        RECT 959.66 37.065 962.47 1659.42 ;
    END
    PORT
      LAYER Metal4 ;
        RECT 970.9 37.065 973.71 1659.42 ;
    END
    PORT
      LAYER Metal4 ;
        RECT 982.14 37.065 984.95 1659.42 ;
    END
    PORT
      LAYER Metal4 ;
        RECT 993.38 37.065 996.19 1659.42 ;
    END
    PORT
      LAYER Metal4 ;
        RECT 1004.62 37.065 1007.43 1659.42 ;
    END
    PORT
      LAYER Metal4 ;
        RECT 1015.86 37.065 1018.67 1659.42 ;
    END
    PORT
      LAYER Metal4 ;
        RECT 1027.1 37.065 1029.91 1659.42 ;
    END
    PORT
      LAYER Metal4 ;
        RECT 1038.34 37.065 1041.15 1659.42 ;
    END
    PORT
      LAYER Metal4 ;
        RECT 1049.58 37.065 1052.39 1659.42 ;
    END
    PORT
      LAYER Metal4 ;
        RECT 1060.82 37.065 1063.63 1659.42 ;
    END
    PORT
      LAYER Metal4 ;
        RECT 1072.06 37.065 1074.87 1659.42 ;
    END
    PORT
      LAYER Metal4 ;
        RECT 1083.3 37.065 1086.11 1659.42 ;
    END
    PORT
      LAYER Metal4 ;
        RECT 1094.54 37.065 1097.35 1659.42 ;
    END
    PORT
      LAYER Metal4 ;
        RECT 1105.78 37.065 1108.59 1659.42 ;
    END
    PORT
      LAYER Metal4 ;
        RECT 1117.02 37.065 1119.83 1659.42 ;
    END
    PORT
      LAYER Metal4 ;
        RECT 1128.26 37.065 1131.07 1659.42 ;
    END
    PORT
      LAYER Metal4 ;
        RECT 1139.5 37.065 1142.31 1659.42 ;
    END
    PORT
      LAYER Metal4 ;
        RECT 1150.74 37.065 1153.55 1659.42 ;
    END
    PORT
      LAYER Metal4 ;
        RECT 1161.98 37.065 1164.79 1659.42 ;
    END
    PORT
      LAYER Metal4 ;
        RECT 1173.22 37.065 1176.03 1659.42 ;
    END
    PORT
      LAYER Metal4 ;
        RECT 1184.46 37.065 1187.27 1659.42 ;
    END
    PORT
      LAYER Metal4 ;
        RECT 1195.7 37.065 1198.51 1659.42 ;
    END
    PORT
      LAYER Metal4 ;
        RECT 1206.94 37.065 1209.75 1659.42 ;
    END
    PORT
      LAYER Metal4 ;
        RECT 1218.18 37.065 1220.99 1659.42 ;
    END
    PORT
      LAYER Metal4 ;
        RECT 1229.42 37.065 1232.23 1659.42 ;
    END
    PORT
      LAYER Metal4 ;
        RECT 1240.66 37.065 1243.47 1659.42 ;
    END
    PORT
      LAYER Metal4 ;
        RECT 1251.9 37.065 1254.71 1659.42 ;
    END
    PORT
      LAYER Metal4 ;
        RECT 1263.14 37.065 1265.95 1659.42 ;
    END
    PORT
      LAYER Metal4 ;
        RECT 1274.38 37.065 1277.19 1659.42 ;
    END
    PORT
      LAYER Metal4 ;
        RECT 1285.62 37.065 1288.43 1659.42 ;
    END
    PORT
      LAYER Metal4 ;
        RECT 1296.86 37.065 1299.67 1659.42 ;
    END
    PORT
      LAYER Metal4 ;
        RECT 1308.1 37.065 1310.91 1659.42 ;
    END
    PORT
      LAYER Metal4 ;
        RECT 1319.34 37.065 1322.15 1659.42 ;
    END
    PORT
      LAYER Metal4 ;
        RECT 1330.58 37.065 1333.39 1659.42 ;
    END
    PORT
      LAYER Metal4 ;
        RECT 1341.82 37.065 1344.63 1659.42 ;
    END
    PORT
      LAYER Metal4 ;
        RECT 1353.06 37.065 1355.87 1659.42 ;
    END
    PORT
      LAYER Metal4 ;
        RECT 1364.3 37.065 1367.11 1659.42 ;
    END
    PORT
      LAYER Metal4 ;
        RECT 1375.54 37.065 1378.35 1659.42 ;
    END
    PORT
      LAYER Metal4 ;
        RECT 1386.78 37.065 1389.59 1659.42 ;
    END
    PORT
      LAYER Metal4 ;
        RECT 1398.02 37.065 1400.83 1659.42 ;
    END
    PORT
      LAYER Metal4 ;
        RECT 1409.26 37.065 1412.07 1659.42 ;
    END
    PORT
      LAYER Metal4 ;
        RECT 1420.5 37.065 1423.31 1659.42 ;
    END
    PORT
      LAYER Metal4 ;
        RECT 1431.74 37.065 1434.55 1659.42 ;
    END
    PORT
      LAYER Metal4 ;
        RECT 1442.98 37.065 1445.79 1659.42 ;
    END
    PORT
      LAYER Metal4 ;
        RECT 1454.22 37.065 1457.03 1659.42 ;
    END
    PORT
      LAYER Metal4 ;
        RECT 1465.46 37.065 1468.27 1659.42 ;
    END
    PORT
      LAYER Metal4 ;
        RECT 1476.7 37.065 1479.51 1659.42 ;
    END
    PORT
      LAYER Metal4 ;
        RECT 1487.94 37.065 1490.75 1659.42 ;
    END
    PORT
      LAYER Metal4 ;
        RECT 1499.18 37.065 1501.99 1659.42 ;
    END
    PORT
      LAYER Metal4 ;
        RECT 1510.42 37.065 1513.23 1659.42 ;
    END
    PORT
      LAYER Metal4 ;
        RECT 1521.66 37.065 1524.47 1659.42 ;
    END
    PORT
      LAYER Metal4 ;
        RECT 1532.9 37.065 1535.71 1659.42 ;
    END
    PORT
      LAYER Metal4 ;
        RECT 1544.14 37.065 1546.95 1659.42 ;
    END
    PORT
      LAYER Metal4 ;
        RECT 1555.38 37.065 1558.19 1659.42 ;
    END
    PORT
      LAYER Metal4 ;
        RECT 1566.62 37.065 1569.43 1659.42 ;
    END
    PORT
      LAYER Metal4 ;
        RECT 1577.86 37.065 1580.67 1659.42 ;
    END
    PORT
      LAYER Metal4 ;
        RECT 1589.1 37.065 1591.91 1659.42 ;
    END
    PORT
      LAYER Metal4 ;
        RECT 1600.34 37.065 1603.15 1659.42 ;
    END
    PORT
      LAYER Metal4 ;
        RECT 1611.58 37.065 1614.39 1659.42 ;
    END
    PORT
      LAYER Metal4 ;
        RECT 1622.82 37.065 1625.63 1659.42 ;
    END
  END VDDARRAY
  PIN VSS
    DIRECTION INOUT ;
    USE GROUND ;
    PORT
      LAYER Metal4 ;
        RECT 21.12 0 23.93 1659.42 ;
    END
    PORT
      LAYER Metal4 ;
        RECT 32.36 0 35.17 1659.42 ;
    END
    PORT
      LAYER Metal4 ;
        RECT 43.6 0 46.41 1659.42 ;
    END
    PORT
      LAYER Metal4 ;
        RECT 54.84 0 57.65 1659.42 ;
    END
    PORT
      LAYER Metal4 ;
        RECT 66.08 0 68.89 1659.42 ;
    END
    PORT
      LAYER Metal4 ;
        RECT 77.32 0 80.13 1659.42 ;
    END
    PORT
      LAYER Metal4 ;
        RECT 88.56 0 91.37 1659.42 ;
    END
    PORT
      LAYER Metal4 ;
        RECT 99.8 0 102.61 1659.42 ;
    END
    PORT
      LAYER Metal4 ;
        RECT 111.04 0 113.85 1659.42 ;
    END
    PORT
      LAYER Metal4 ;
        RECT 122.28 0 125.09 1659.42 ;
    END
    PORT
      LAYER Metal4 ;
        RECT 133.52 0 136.33 1659.42 ;
    END
    PORT
      LAYER Metal4 ;
        RECT 144.76 0 147.57 1659.42 ;
    END
    PORT
      LAYER Metal4 ;
        RECT 156 0 158.81 1659.42 ;
    END
    PORT
      LAYER Metal4 ;
        RECT 167.24 0 170.05 1659.42 ;
    END
    PORT
      LAYER Metal4 ;
        RECT 178.48 0 181.29 1659.42 ;
    END
    PORT
      LAYER Metal4 ;
        RECT 189.72 0 192.53 1659.42 ;
    END
    PORT
      LAYER Metal4 ;
        RECT 200.96 0 203.77 1659.42 ;
    END
    PORT
      LAYER Metal4 ;
        RECT 212.2 0 215.01 1659.42 ;
    END
    PORT
      LAYER Metal4 ;
        RECT 223.44 0 226.25 1659.42 ;
    END
    PORT
      LAYER Metal4 ;
        RECT 234.68 0 237.49 1659.42 ;
    END
    PORT
      LAYER Metal4 ;
        RECT 245.92 0 248.73 1659.42 ;
    END
    PORT
      LAYER Metal4 ;
        RECT 257.16 0 259.97 1659.42 ;
    END
    PORT
      LAYER Metal4 ;
        RECT 268.4 0 271.21 1659.42 ;
    END
    PORT
      LAYER Metal4 ;
        RECT 279.64 0 282.45 1659.42 ;
    END
    PORT
      LAYER Metal4 ;
        RECT 290.88 0 293.69 1659.42 ;
    END
    PORT
      LAYER Metal4 ;
        RECT 302.12 0 304.93 1659.42 ;
    END
    PORT
      LAYER Metal4 ;
        RECT 313.36 0 316.17 1659.42 ;
    END
    PORT
      LAYER Metal4 ;
        RECT 324.6 0 327.41 1659.42 ;
    END
    PORT
      LAYER Metal4 ;
        RECT 335.84 0 338.65 1659.42 ;
    END
    PORT
      LAYER Metal4 ;
        RECT 347.08 0 349.89 1659.42 ;
    END
    PORT
      LAYER Metal4 ;
        RECT 358.32 0 361.13 1659.42 ;
    END
    PORT
      LAYER Metal4 ;
        RECT 369.56 0 372.37 1659.42 ;
    END
    PORT
      LAYER Metal4 ;
        RECT 380.8 0 383.61 1659.42 ;
    END
    PORT
      LAYER Metal4 ;
        RECT 392.04 0 394.85 1659.42 ;
    END
    PORT
      LAYER Metal4 ;
        RECT 403.28 0 406.09 1659.42 ;
    END
    PORT
      LAYER Metal4 ;
        RECT 414.52 0 417.33 1659.42 ;
    END
    PORT
      LAYER Metal4 ;
        RECT 425.76 0 428.57 1659.42 ;
    END
    PORT
      LAYER Metal4 ;
        RECT 437 0 439.81 1659.42 ;
    END
    PORT
      LAYER Metal4 ;
        RECT 448.24 0 451.05 1659.42 ;
    END
    PORT
      LAYER Metal4 ;
        RECT 459.48 0 462.29 1659.42 ;
    END
    PORT
      LAYER Metal4 ;
        RECT 470.72 0 473.53 1659.42 ;
    END
    PORT
      LAYER Metal4 ;
        RECT 481.96 0 484.77 1659.42 ;
    END
    PORT
      LAYER Metal4 ;
        RECT 493.2 0 496.01 1659.42 ;
    END
    PORT
      LAYER Metal4 ;
        RECT 504.44 0 507.25 1659.42 ;
    END
    PORT
      LAYER Metal4 ;
        RECT 515.68 0 518.49 1659.42 ;
    END
    PORT
      LAYER Metal4 ;
        RECT 526.92 0 529.73 1659.42 ;
    END
    PORT
      LAYER Metal4 ;
        RECT 538.16 0 540.97 1659.42 ;
    END
    PORT
      LAYER Metal4 ;
        RECT 549.4 0 552.21 1659.42 ;
    END
    PORT
      LAYER Metal4 ;
        RECT 560.64 0 563.45 1659.42 ;
    END
    PORT
      LAYER Metal4 ;
        RECT 571.88 0 574.69 1659.42 ;
    END
    PORT
      LAYER Metal4 ;
        RECT 583.12 0 585.93 1659.42 ;
    END
    PORT
      LAYER Metal4 ;
        RECT 594.36 0 597.17 1659.42 ;
    END
    PORT
      LAYER Metal4 ;
        RECT 605.6 0 608.41 1659.42 ;
    END
    PORT
      LAYER Metal4 ;
        RECT 616.84 0 619.65 1659.42 ;
    END
    PORT
      LAYER Metal4 ;
        RECT 628.08 0 630.89 1659.42 ;
    END
    PORT
      LAYER Metal4 ;
        RECT 639.32 0 642.13 1659.42 ;
    END
    PORT
      LAYER Metal4 ;
        RECT 650.56 0 653.37 1659.42 ;
    END
    PORT
      LAYER Metal4 ;
        RECT 661.8 0 664.61 1659.42 ;
    END
    PORT
      LAYER Metal4 ;
        RECT 673.04 0 675.85 1659.42 ;
    END
    PORT
      LAYER Metal4 ;
        RECT 684.28 0 687.09 1659.42 ;
    END
    PORT
      LAYER Metal4 ;
        RECT 695.52 0 698.33 1659.42 ;
    END
    PORT
      LAYER Metal4 ;
        RECT 706.76 0 709.57 1659.42 ;
    END
    PORT
      LAYER Metal4 ;
        RECT 718 0 720.81 1659.42 ;
    END
    PORT
      LAYER Metal4 ;
        RECT 729.24 0 732.05 1659.42 ;
    END
    PORT
      LAYER Metal4 ;
        RECT 740.48 0 743.29 1659.42 ;
    END
    PORT
      LAYER Metal4 ;
        RECT 751.72 0 754.53 1659.42 ;
    END
    PORT
      LAYER Metal4 ;
        RECT 762.96 0 765.77 1659.42 ;
    END
    PORT
      LAYER Metal4 ;
        RECT 774.2 0 777.01 1659.42 ;
    END
    PORT
      LAYER Metal4 ;
        RECT 785.44 0 788.25 1659.42 ;
    END
    PORT
      LAYER Metal4 ;
        RECT 796.68 0 799.49 1659.42 ;
    END
    PORT
      LAYER Metal4 ;
        RECT 807.92 0 810.73 1659.42 ;
    END
    PORT
      LAYER Metal4 ;
        RECT 819.16 0 821.97 1659.42 ;
    END
    PORT
      LAYER Metal4 ;
        RECT 830.4 0 833.21 1659.42 ;
    END
    PORT
      LAYER Metal4 ;
        RECT 841.64 0 844.45 1659.42 ;
    END
    PORT
      LAYER Metal4 ;
        RECT 852.88 0 855.69 1659.42 ;
    END
    PORT
      LAYER Metal4 ;
        RECT 864.12 0 866.93 1659.42 ;
    END
    PORT
      LAYER Metal4 ;
        RECT 875.36 0 878.17 1659.42 ;
    END
    PORT
      LAYER Metal4 ;
        RECT 886.6 0 889.41 1659.42 ;
    END
    PORT
      LAYER Metal4 ;
        RECT 897.84 0 900.65 1659.42 ;
    END
    PORT
      LAYER Metal4 ;
        RECT 909.08 0 911.89 1659.42 ;
    END
    PORT
      LAYER Metal4 ;
        RECT 920.32 0 923.13 1659.42 ;
    END
    PORT
      LAYER Metal4 ;
        RECT 931.56 0 934.37 1659.42 ;
    END
    PORT
      LAYER Metal4 ;
        RECT 942.8 0 945.61 1659.42 ;
    END
    PORT
      LAYER Metal4 ;
        RECT 954.04 0 956.85 1659.42 ;
    END
    PORT
      LAYER Metal4 ;
        RECT 965.28 0 968.09 1659.42 ;
    END
    PORT
      LAYER Metal4 ;
        RECT 976.52 0 979.33 1659.42 ;
    END
    PORT
      LAYER Metal4 ;
        RECT 987.76 0 990.57 1659.42 ;
    END
    PORT
      LAYER Metal4 ;
        RECT 999 0 1001.81 1659.42 ;
    END
    PORT
      LAYER Metal4 ;
        RECT 1010.24 0 1013.05 1659.42 ;
    END
    PORT
      LAYER Metal4 ;
        RECT 1021.48 0 1024.29 1659.42 ;
    END
    PORT
      LAYER Metal4 ;
        RECT 1032.72 0 1035.53 1659.42 ;
    END
    PORT
      LAYER Metal4 ;
        RECT 1043.96 0 1046.77 1659.42 ;
    END
    PORT
      LAYER Metal4 ;
        RECT 1055.2 0 1058.01 1659.42 ;
    END
    PORT
      LAYER Metal4 ;
        RECT 1066.44 0 1069.25 1659.42 ;
    END
    PORT
      LAYER Metal4 ;
        RECT 1077.68 0 1080.49 1659.42 ;
    END
    PORT
      LAYER Metal4 ;
        RECT 1088.92 0 1091.73 1659.42 ;
    END
    PORT
      LAYER Metal4 ;
        RECT 1100.16 0 1102.97 1659.42 ;
    END
    PORT
      LAYER Metal4 ;
        RECT 1111.4 0 1114.21 1659.42 ;
    END
    PORT
      LAYER Metal4 ;
        RECT 1122.64 0 1125.45 1659.42 ;
    END
    PORT
      LAYER Metal4 ;
        RECT 1133.88 0 1136.69 1659.42 ;
    END
    PORT
      LAYER Metal4 ;
        RECT 1145.12 0 1147.93 1659.42 ;
    END
    PORT
      LAYER Metal4 ;
        RECT 1156.36 0 1159.17 1659.42 ;
    END
    PORT
      LAYER Metal4 ;
        RECT 1167.6 0 1170.41 1659.42 ;
    END
    PORT
      LAYER Metal4 ;
        RECT 1178.84 0 1181.65 1659.42 ;
    END
    PORT
      LAYER Metal4 ;
        RECT 1190.08 0 1192.89 1659.42 ;
    END
    PORT
      LAYER Metal4 ;
        RECT 1201.32 0 1204.13 1659.42 ;
    END
    PORT
      LAYER Metal4 ;
        RECT 1212.56 0 1215.37 1659.42 ;
    END
    PORT
      LAYER Metal4 ;
        RECT 1223.8 0 1226.61 1659.42 ;
    END
    PORT
      LAYER Metal4 ;
        RECT 1235.04 0 1237.85 1659.42 ;
    END
    PORT
      LAYER Metal4 ;
        RECT 1246.28 0 1249.09 1659.42 ;
    END
    PORT
      LAYER Metal4 ;
        RECT 1257.52 0 1260.33 1659.42 ;
    END
    PORT
      LAYER Metal4 ;
        RECT 1268.76 0 1271.57 1659.42 ;
    END
    PORT
      LAYER Metal4 ;
        RECT 1280 0 1282.81 1659.42 ;
    END
    PORT
      LAYER Metal4 ;
        RECT 1291.24 0 1294.05 1659.42 ;
    END
    PORT
      LAYER Metal4 ;
        RECT 1302.48 0 1305.29 1659.42 ;
    END
    PORT
      LAYER Metal4 ;
        RECT 1313.72 0 1316.53 1659.42 ;
    END
    PORT
      LAYER Metal4 ;
        RECT 1324.96 0 1327.77 1659.42 ;
    END
    PORT
      LAYER Metal4 ;
        RECT 1336.2 0 1339.01 1659.42 ;
    END
    PORT
      LAYER Metal4 ;
        RECT 1347.44 0 1350.25 1659.42 ;
    END
    PORT
      LAYER Metal4 ;
        RECT 1358.68 0 1361.49 1659.42 ;
    END
    PORT
      LAYER Metal4 ;
        RECT 1369.92 0 1372.73 1659.42 ;
    END
    PORT
      LAYER Metal4 ;
        RECT 1381.16 0 1383.97 1659.42 ;
    END
    PORT
      LAYER Metal4 ;
        RECT 1392.4 0 1395.21 1659.42 ;
    END
    PORT
      LAYER Metal4 ;
        RECT 1403.64 0 1406.45 1659.42 ;
    END
    PORT
      LAYER Metal4 ;
        RECT 1414.88 0 1417.69 1659.42 ;
    END
    PORT
      LAYER Metal4 ;
        RECT 1426.12 0 1428.93 1659.42 ;
    END
    PORT
      LAYER Metal4 ;
        RECT 1437.36 0 1440.17 1659.42 ;
    END
    PORT
      LAYER Metal4 ;
        RECT 1448.6 0 1451.41 1659.42 ;
    END
    PORT
      LAYER Metal4 ;
        RECT 1459.84 0 1462.65 1659.42 ;
    END
    PORT
      LAYER Metal4 ;
        RECT 1471.08 0 1473.89 1659.42 ;
    END
    PORT
      LAYER Metal4 ;
        RECT 1482.32 0 1485.13 1659.42 ;
    END
    PORT
      LAYER Metal4 ;
        RECT 1493.56 0 1496.37 1659.42 ;
    END
    PORT
      LAYER Metal4 ;
        RECT 1504.8 0 1507.61 1659.42 ;
    END
    PORT
      LAYER Metal4 ;
        RECT 1516.04 0 1518.85 1659.42 ;
    END
    PORT
      LAYER Metal4 ;
        RECT 1527.28 0 1530.09 1659.42 ;
    END
    PORT
      LAYER Metal4 ;
        RECT 1538.52 0 1541.33 1659.42 ;
    END
    PORT
      LAYER Metal4 ;
        RECT 1549.76 0 1552.57 1659.42 ;
    END
    PORT
      LAYER Metal4 ;
        RECT 1561 0 1563.81 1659.42 ;
    END
    PORT
      LAYER Metal4 ;
        RECT 1572.24 0 1575.05 1659.42 ;
    END
    PORT
      LAYER Metal4 ;
        RECT 1583.48 0 1586.29 1659.42 ;
    END
    PORT
      LAYER Metal4 ;
        RECT 1594.72 0 1597.53 1659.42 ;
    END
    PORT
      LAYER Metal4 ;
        RECT 1605.96 0 1608.77 1659.42 ;
    END
    PORT
      LAYER Metal4 ;
        RECT 1617.2 0 1620.01 1659.42 ;
    END
    PORT
      LAYER Metal4 ;
        RECT 1628.44 0 1631.25 1659.42 ;
    END
  END VSS
  OBS
    LAYER Metal1 ;
      RECT 0 0 1657.92 1659.42 ;
    LAYER Metal2 ;
      RECT 0 1 1657.92 1659.42 ;
    LAYER Metal3 ;
      RECT 0 1 1657.92 1659.42 ;
    LAYER Metal4 ;
      RECT 0 0 15.2 1659.42 ;
      RECT 18.61 0 20.82 1659.42 ;
      RECT 24.23 0 26.44 1659.42 ;
      RECT 29.85 0 32.06 1659.42 ;
      RECT 35.47 0 37.68 1659.42 ;
      RECT 41.09 0 43.3 1659.42 ;
      RECT 46.71 0 48.92 1659.42 ;
      RECT 52.33 0 54.54 1659.42 ;
      RECT 57.95 0 60.16 1659.42 ;
      RECT 63.57 0 65.78 1659.42 ;
      RECT 69.19 0 71.4 1659.42 ;
      RECT 74.81 0 77.02 1659.42 ;
      RECT 80.43 0 82.64 1659.42 ;
      RECT 86.05 0 88.26 1659.42 ;
      RECT 91.67 0 93.88 1659.42 ;
      RECT 97.29 0 99.5 1659.42 ;
      RECT 102.91 0 105.12 1659.42 ;
      RECT 108.53 0 110.74 1659.42 ;
      RECT 114.15 0 116.36 1659.42 ;
      RECT 119.77 0 121.98 1659.42 ;
      RECT 125.39 0 127.6 1659.42 ;
      RECT 131.01 0 133.22 1659.42 ;
      RECT 136.63 0 138.84 1659.42 ;
      RECT 142.25 0 144.46 1659.42 ;
      RECT 147.87 0 150.08 1659.42 ;
      RECT 153.49 0 155.7 1659.42 ;
      RECT 159.11 0 161.32 1659.42 ;
      RECT 164.73 0 166.94 1659.42 ;
      RECT 170.35 0 172.56 1659.42 ;
      RECT 175.97 0 178.18 1659.42 ;
      RECT 181.59 0 183.8 1659.42 ;
      RECT 187.21 0 189.42 1659.42 ;
      RECT 192.83 0 195.04 1659.42 ;
      RECT 198.45 0 200.66 1659.42 ;
      RECT 204.07 0 206.28 1659.42 ;
      RECT 209.69 0 211.9 1659.42 ;
      RECT 215.31 0 217.52 1659.42 ;
      RECT 220.93 0 223.14 1659.42 ;
      RECT 226.55 0 228.76 1659.42 ;
      RECT 232.17 0 234.38 1659.42 ;
      RECT 237.79 0 240 1659.42 ;
      RECT 243.41 0 245.62 1659.42 ;
      RECT 249.03 0 251.24 1659.42 ;
      RECT 254.65 0 256.86 1659.42 ;
      RECT 260.27 0 262.48 1659.42 ;
      RECT 265.89 0 268.1 1659.42 ;
      RECT 271.51 0 273.72 1659.42 ;
      RECT 277.13 0 279.34 1659.42 ;
      RECT 282.75 0 284.96 1659.42 ;
      RECT 288.37 0 290.58 1659.42 ;
      RECT 293.99 0 296.2 1659.42 ;
      RECT 299.61 0 301.82 1659.42 ;
      RECT 305.23 0 307.44 1659.42 ;
      RECT 310.85 0 313.06 1659.42 ;
      RECT 316.47 0 318.68 1659.42 ;
      RECT 322.09 0 324.3 1659.42 ;
      RECT 327.71 0 329.92 1659.42 ;
      RECT 333.33 0 335.54 1659.42 ;
      RECT 338.95 0 341.16 1659.42 ;
      RECT 344.57 0 346.78 1659.42 ;
      RECT 350.19 0 352.4 1659.42 ;
      RECT 355.81 0 358.02 1659.42 ;
      RECT 361.43 0 363.64 1659.42 ;
      RECT 367.05 0 369.26 1659.42 ;
      RECT 372.67 0 374.88 1659.42 ;
      RECT 378.29 0 380.5 1659.42 ;
      RECT 383.91 0 386.12 1659.42 ;
      RECT 389.53 0 391.74 1659.42 ;
      RECT 395.15 0 397.36 1659.42 ;
      RECT 400.77 0 402.98 1659.42 ;
      RECT 406.39 0 408.6 1659.42 ;
      RECT 412.01 0 414.22 1659.42 ;
      RECT 417.63 0 419.84 1659.42 ;
      RECT 423.25 0 425.46 1659.42 ;
      RECT 428.87 0 431.08 1659.42 ;
      RECT 434.49 0 436.7 1659.42 ;
      RECT 440.11 0 442.32 1659.42 ;
      RECT 445.73 0 447.94 1659.42 ;
      RECT 451.35 0 453.56 1659.42 ;
      RECT 456.97 0 459.18 1659.42 ;
      RECT 462.59 0 464.8 1659.42 ;
      RECT 468.21 0 470.42 1659.42 ;
      RECT 473.83 0 476.04 1659.42 ;
      RECT 479.45 0 481.66 1659.42 ;
      RECT 485.07 0 487.28 1659.42 ;
      RECT 490.69 0 492.9 1659.42 ;
      RECT 496.31 0 498.52 1659.42 ;
      RECT 501.93 0 504.14 1659.42 ;
      RECT 507.55 0 509.76 1659.42 ;
      RECT 513.17 0 515.38 1659.42 ;
      RECT 518.79 0 521 1659.42 ;
      RECT 524.41 0 526.62 1659.42 ;
      RECT 530.03 0 532.24 1659.42 ;
      RECT 535.65 0 537.86 1659.42 ;
      RECT 541.27 0 543.48 1659.42 ;
      RECT 546.89 0 549.1 1659.42 ;
      RECT 552.51 0 554.72 1659.42 ;
      RECT 558.13 0 560.34 1659.42 ;
      RECT 563.75 0 565.96 1659.42 ;
      RECT 569.37 0 571.58 1659.42 ;
      RECT 574.99 0 577.2 1659.42 ;
      RECT 580.61 0 582.82 1659.42 ;
      RECT 586.23 0 588.44 1659.42 ;
      RECT 591.85 0 594.06 1659.42 ;
      RECT 597.47 0 599.68 1659.42 ;
      RECT 603.09 0 605.3 1659.42 ;
      RECT 608.71 0 610.92 1659.42 ;
      RECT 614.33 0 616.54 1659.42 ;
      RECT 619.95 0 622.16 1659.42 ;
      RECT 625.57 0 627.78 1659.42 ;
      RECT 631.19 0 633.4 1659.42 ;
      RECT 636.81 0 639.02 1659.42 ;
      RECT 642.43 0 644.64 1659.42 ;
      RECT 648.05 0 650.26 1659.42 ;
      RECT 653.67 0 655.88 1659.42 ;
      RECT 659.29 0 661.5 1659.42 ;
      RECT 664.91 0 667.12 1659.42 ;
      RECT 670.53 0 672.74 1659.42 ;
      RECT 676.15 0 678.36 1659.42 ;
      RECT 681.77 0 683.98 1659.42 ;
      RECT 687.39 0 689.6 1659.42 ;
      RECT 693.01 0 695.22 1659.42 ;
      RECT 698.63 0 700.84 1659.42 ;
      RECT 704.25 0 706.46 1659.42 ;
      RECT 709.87 0 712.08 1659.42 ;
      RECT 715.49 0 717.7 1659.42 ;
      RECT 721.11 0 723.32 1659.42 ;
      RECT 726.73 0 728.94 1659.42 ;
      RECT 732.35 0 734.56 1659.42 ;
      RECT 737.97 0 740.18 1659.42 ;
      RECT 743.59 0 745.8 1659.42 ;
      RECT 749.21 0 751.42 1659.42 ;
      RECT 754.83 0 757.04 1659.42 ;
      RECT 760.45 0 762.66 1659.42 ;
      RECT 766.07 0 768.28 1659.42 ;
      RECT 771.69 0 773.9 1659.42 ;
      RECT 777.31 0 779.52 1659.42 ;
      RECT 782.93 0 785.14 1659.42 ;
      RECT 788.55 0 790.76 1659.42 ;
      RECT 794.17 0 796.38 1659.42 ;
      RECT 799.79 0 802 1659.42 ;
      RECT 805.41 0 807.62 1659.42 ;
      RECT 811.03 0 813.24 1659.42 ;
      RECT 816.65 0 818.86 1659.42 ;
      RECT 822.27 0 824.48 1659.42 ;
      RECT 827.89 0 830.1 1659.42 ;
      RECT 833.51 0 835.72 1659.42 ;
      RECT 839.13 0 841.34 1659.42 ;
      RECT 844.75 0 846.96 1659.42 ;
      RECT 850.37 0 852.58 1659.42 ;
      RECT 855.99 0 858.2 1659.42 ;
      RECT 861.61 0 863.82 1659.42 ;
      RECT 867.23 0 869.44 1659.42 ;
      RECT 872.85 0 875.06 1659.42 ;
      RECT 878.47 0 880.68 1659.42 ;
      RECT 884.09 0 886.3 1659.42 ;
      RECT 889.71 0 891.92 1659.42 ;
      RECT 895.33 0 897.54 1659.42 ;
      RECT 900.95 0 903.16 1659.42 ;
      RECT 906.57 0 908.78 1659.42 ;
      RECT 912.19 0 914.4 1659.42 ;
      RECT 917.81 0 920.02 1659.42 ;
      RECT 923.43 0 925.64 1659.42 ;
      RECT 929.05 0 931.26 1659.42 ;
      RECT 934.67 0 936.88 1659.42 ;
      RECT 940.29 0 942.5 1659.42 ;
      RECT 945.91 0 948.12 1659.42 ;
      RECT 951.53 0 953.74 1659.42 ;
      RECT 957.15 0 959.36 1659.42 ;
      RECT 962.77 0 964.98 1659.42 ;
      RECT 968.39 0 970.6 1659.42 ;
      RECT 974.01 0 976.22 1659.42 ;
      RECT 979.63 0 981.84 1659.42 ;
      RECT 985.25 0 987.46 1659.42 ;
      RECT 990.87 0 993.08 1659.42 ;
      RECT 996.49 0 998.7 1659.42 ;
      RECT 1002.11 0 1004.32 1659.42 ;
      RECT 1007.73 0 1009.94 1659.42 ;
      RECT 1013.35 0 1015.56 1659.42 ;
      RECT 1018.97 0 1021.18 1659.42 ;
      RECT 1024.59 0 1026.8 1659.42 ;
      RECT 1030.21 0 1032.42 1659.42 ;
      RECT 1035.83 0 1038.04 1659.42 ;
      RECT 1041.45 0 1043.66 1659.42 ;
      RECT 1047.07 0 1049.28 1659.42 ;
      RECT 1052.69 0 1054.9 1659.42 ;
      RECT 1058.31 0 1060.52 1659.42 ;
      RECT 1063.93 0 1066.14 1659.42 ;
      RECT 1069.55 0 1071.76 1659.42 ;
      RECT 1075.17 0 1077.38 1659.42 ;
      RECT 1080.79 0 1083 1659.42 ;
      RECT 1086.41 0 1088.62 1659.42 ;
      RECT 1092.03 0 1094.24 1659.42 ;
      RECT 1097.65 0 1099.86 1659.42 ;
      RECT 1103.27 0 1105.48 1659.42 ;
      RECT 1108.89 0 1111.1 1659.42 ;
      RECT 1114.51 0 1116.72 1659.42 ;
      RECT 1120.13 0 1122.34 1659.42 ;
      RECT 1125.75 0 1127.96 1659.42 ;
      RECT 1131.37 0 1133.58 1659.42 ;
      RECT 1136.99 0 1139.2 1659.42 ;
      RECT 1142.61 0 1144.82 1659.42 ;
      RECT 1148.23 0 1150.44 1659.42 ;
      RECT 1153.85 0 1156.06 1659.42 ;
      RECT 1159.47 0 1161.68 1659.42 ;
      RECT 1165.09 0 1167.3 1659.42 ;
      RECT 1170.71 0 1172.92 1659.42 ;
      RECT 1176.33 0 1178.54 1659.42 ;
      RECT 1181.95 0 1184.16 1659.42 ;
      RECT 1187.57 0 1189.78 1659.42 ;
      RECT 1193.19 0 1195.4 1659.42 ;
      RECT 1198.81 0 1201.02 1659.42 ;
      RECT 1204.43 0 1206.64 1659.42 ;
      RECT 1210.05 0 1212.26 1659.42 ;
      RECT 1215.67 0 1217.88 1659.42 ;
      RECT 1221.29 0 1223.5 1659.42 ;
      RECT 1226.91 0 1229.12 1659.42 ;
      RECT 1232.53 0 1234.74 1659.42 ;
      RECT 1238.15 0 1240.36 1659.42 ;
      RECT 1243.77 0 1245.98 1659.42 ;
      RECT 1249.39 0 1251.6 1659.42 ;
      RECT 1255.01 0 1257.22 1659.42 ;
      RECT 1260.63 0 1262.84 1659.42 ;
      RECT 1266.25 0 1268.46 1659.42 ;
      RECT 1271.87 0 1274.08 1659.42 ;
      RECT 1277.49 0 1279.7 1659.42 ;
      RECT 1283.11 0 1285.32 1659.42 ;
      RECT 1288.73 0 1290.94 1659.42 ;
      RECT 1294.35 0 1296.56 1659.42 ;
      RECT 1299.97 0 1302.18 1659.42 ;
      RECT 1305.59 0 1307.8 1659.42 ;
      RECT 1311.21 0 1313.42 1659.42 ;
      RECT 1316.83 0 1319.04 1659.42 ;
      RECT 1322.45 0 1324.66 1659.42 ;
      RECT 1328.07 0 1330.28 1659.42 ;
      RECT 1333.69 0 1335.9 1659.42 ;
      RECT 1339.31 0 1341.52 1659.42 ;
      RECT 1344.93 0 1347.14 1659.42 ;
      RECT 1350.55 0 1352.76 1659.42 ;
      RECT 1356.17 0 1358.38 1659.42 ;
      RECT 1361.79 0 1364 1659.42 ;
      RECT 1367.41 0 1369.62 1659.42 ;
      RECT 1373.03 0 1375.24 1659.42 ;
      RECT 1378.65 0 1380.86 1659.42 ;
      RECT 1384.27 0 1386.48 1659.42 ;
      RECT 1389.89 0 1392.1 1659.42 ;
      RECT 1395.51 0 1397.72 1659.42 ;
      RECT 1401.13 0 1403.34 1659.42 ;
      RECT 1406.75 0 1408.96 1659.42 ;
      RECT 1412.37 0 1414.58 1659.42 ;
      RECT 1417.99 0 1420.2 1659.42 ;
      RECT 1423.61 0 1425.82 1659.42 ;
      RECT 1429.23 0 1431.44 1659.42 ;
      RECT 1434.85 0 1437.06 1659.42 ;
      RECT 1440.47 0 1442.68 1659.42 ;
      RECT 1446.09 0 1448.3 1659.42 ;
      RECT 1451.71 0 1453.92 1659.42 ;
      RECT 1457.33 0 1459.54 1659.42 ;
      RECT 1462.95 0 1465.16 1659.42 ;
      RECT 1468.57 0 1470.78 1659.42 ;
      RECT 1474.19 0 1476.4 1659.42 ;
      RECT 1479.81 0 1482.02 1659.42 ;
      RECT 1485.43 0 1487.64 1659.42 ;
      RECT 1491.05 0 1493.26 1659.42 ;
      RECT 1496.67 0 1498.88 1659.42 ;
      RECT 1502.29 0 1504.5 1659.42 ;
      RECT 1507.91 0 1510.12 1659.42 ;
      RECT 1513.53 0 1515.74 1659.42 ;
      RECT 1519.15 0 1521.36 1659.42 ;
      RECT 1524.77 0 1526.98 1659.42 ;
      RECT 1530.39 0 1532.6 1659.42 ;
      RECT 1536.01 0 1538.22 1659.42 ;
      RECT 1541.63 0 1543.84 1659.42 ;
      RECT 1547.25 0 1549.46 1659.42 ;
      RECT 1552.87 0 1555.08 1659.42 ;
      RECT 1558.49 0 1560.7 1659.42 ;
      RECT 1564.11 0 1566.32 1659.42 ;
      RECT 1569.73 0 1571.94 1659.42 ;
      RECT 1575.35 0 1577.56 1659.42 ;
      RECT 1580.97 0 1583.18 1659.42 ;
      RECT 1586.59 0 1588.8 1659.42 ;
      RECT 1592.21 0 1594.42 1659.42 ;
      RECT 1597.83 0 1600.04 1659.42 ;
      RECT 1603.45 0 1605.66 1659.42 ;
      RECT 1609.07 0 1611.28 1659.42 ;
      RECT 1614.69 0 1616.9 1659.42 ;
      RECT 1620.31 0 1622.52 1659.42 ;
      RECT 1625.93 0 1628.14 1659.42 ;
      RECT 1631.55 0 1657.92 1659.42 ;
      RECT 15.5 30.725 18.31 36.765 ;
      RECT 26.74 30.725 29.55 36.765 ;
      RECT 37.98 30.725 40.79 36.765 ;
      RECT 49.22 30.725 52.03 36.765 ;
      RECT 60.46 30.725 63.27 36.765 ;
      RECT 71.7 30.725 74.51 36.765 ;
      RECT 82.94 30.725 85.75 36.765 ;
      RECT 94.18 30.725 96.99 36.765 ;
      RECT 105.42 30.725 108.23 36.765 ;
      RECT 116.66 30.725 119.47 36.765 ;
      RECT 127.9 30.725 130.71 36.765 ;
      RECT 139.14 30.725 141.95 36.765 ;
      RECT 150.38 30.725 153.19 36.765 ;
      RECT 161.62 30.725 164.43 36.765 ;
      RECT 172.86 30.725 175.67 36.765 ;
      RECT 184.1 30.725 186.91 36.765 ;
      RECT 195.34 30.725 198.15 36.765 ;
      RECT 206.58 30.725 209.39 36.765 ;
      RECT 217.82 30.725 220.63 36.765 ;
      RECT 229.06 30.725 231.87 36.765 ;
      RECT 240.3 30.725 243.11 36.765 ;
      RECT 251.54 30.725 254.35 36.765 ;
      RECT 262.78 30.725 265.59 36.765 ;
      RECT 274.02 30.725 276.83 36.765 ;
      RECT 285.26 30.725 288.07 36.765 ;
      RECT 296.5 30.725 299.31 36.765 ;
      RECT 307.74 30.725 310.55 36.765 ;
      RECT 318.98 30.725 321.79 36.765 ;
      RECT 330.22 30.725 333.03 36.765 ;
      RECT 341.46 30.725 344.27 36.765 ;
      RECT 352.7 30.725 355.51 36.765 ;
      RECT 363.94 30.725 366.75 36.765 ;
      RECT 375.18 30.725 377.99 36.765 ;
      RECT 386.42 30.725 389.23 36.765 ;
      RECT 397.66 30.725 400.47 36.765 ;
      RECT 408.9 30.725 411.71 36.765 ;
      RECT 420.14 30.725 422.95 36.765 ;
      RECT 431.38 30.725 434.19 36.765 ;
      RECT 442.62 30.725 445.43 36.765 ;
      RECT 453.86 30.725 456.67 36.765 ;
      RECT 465.1 30.725 467.91 36.765 ;
      RECT 476.34 30.725 479.15 36.765 ;
      RECT 487.58 30.725 490.39 36.765 ;
      RECT 498.82 30.725 501.63 36.765 ;
      RECT 510.06 30.725 512.87 36.765 ;
      RECT 521.3 30.725 524.11 36.765 ;
      RECT 532.54 30.725 535.35 36.765 ;
      RECT 543.78 30.725 546.59 36.765 ;
      RECT 555.02 30.725 557.83 36.765 ;
      RECT 566.26 30.725 569.07 36.765 ;
      RECT 577.5 30.725 580.31 36.765 ;
      RECT 588.74 30.725 591.55 36.765 ;
      RECT 599.98 30.725 602.79 36.765 ;
      RECT 611.22 30.725 614.03 36.765 ;
      RECT 622.46 30.725 625.27 36.765 ;
      RECT 633.7 30.725 636.51 36.765 ;
      RECT 644.94 30.725 647.75 36.765 ;
      RECT 656.18 30.725 658.99 36.765 ;
      RECT 667.42 30.725 670.23 36.765 ;
      RECT 678.66 30.725 681.47 36.765 ;
      RECT 689.9 30.725 692.71 36.765 ;
      RECT 701.14 30.725 703.95 36.765 ;
      RECT 712.38 30.725 715.19 36.765 ;
      RECT 723.62 30.725 726.43 36.765 ;
      RECT 734.86 30.725 737.67 36.765 ;
      RECT 746.1 30.725 748.91 36.765 ;
      RECT 757.34 30.725 760.15 36.765 ;
      RECT 768.58 30.725 771.39 36.765 ;
      RECT 779.82 30.725 782.63 36.765 ;
      RECT 791.06 30.725 793.87 36.765 ;
      RECT 802.3 30.725 805.11 36.765 ;
      RECT 813.54 30.725 816.35 36.765 ;
      RECT 824.78 30.725 827.59 36.765 ;
      RECT 836.02 30.725 838.83 36.765 ;
      RECT 847.26 30.725 850.07 36.765 ;
      RECT 858.5 30.725 861.31 36.765 ;
      RECT 869.74 30.725 872.55 36.765 ;
      RECT 880.98 30.725 883.79 36.765 ;
      RECT 892.22 30.725 895.03 36.765 ;
      RECT 903.46 30.725 906.27 36.765 ;
      RECT 914.7 30.725 917.51 36.765 ;
      RECT 925.94 30.725 928.75 36.765 ;
      RECT 937.18 30.725 939.99 36.765 ;
      RECT 948.42 30.725 951.23 36.765 ;
      RECT 959.66 30.725 962.47 36.765 ;
      RECT 970.9 30.725 973.71 36.765 ;
      RECT 982.14 30.725 984.95 36.765 ;
      RECT 993.38 30.725 996.19 36.765 ;
      RECT 1004.62 30.725 1007.43 36.765 ;
      RECT 1015.86 30.725 1018.67 36.765 ;
      RECT 1027.1 30.725 1029.91 36.765 ;
      RECT 1038.34 30.725 1041.15 36.765 ;
      RECT 1049.58 30.725 1052.39 36.765 ;
      RECT 1060.82 30.725 1063.63 36.765 ;
      RECT 1072.06 30.725 1074.87 36.765 ;
      RECT 1083.3 30.725 1086.11 36.765 ;
      RECT 1094.54 30.725 1097.35 36.765 ;
      RECT 1105.78 30.725 1108.59 36.765 ;
      RECT 1117.02 30.725 1119.83 36.765 ;
      RECT 1128.26 30.725 1131.07 36.765 ;
      RECT 1139.5 30.725 1142.31 36.765 ;
      RECT 1150.74 30.725 1153.55 36.765 ;
      RECT 1161.98 30.725 1164.79 36.765 ;
      RECT 1173.22 30.725 1176.03 36.765 ;
      RECT 1184.46 30.725 1187.27 36.765 ;
      RECT 1195.7 30.725 1198.51 36.765 ;
      RECT 1206.94 30.725 1209.75 36.765 ;
      RECT 1218.18 30.725 1220.99 36.765 ;
      RECT 1229.42 30.725 1232.23 36.765 ;
      RECT 1240.66 30.725 1243.47 36.765 ;
      RECT 1251.9 30.725 1254.71 36.765 ;
      RECT 1263.14 30.725 1265.95 36.765 ;
      RECT 1274.38 30.725 1277.19 36.765 ;
      RECT 1285.62 30.725 1288.43 36.765 ;
      RECT 1296.86 30.725 1299.67 36.765 ;
      RECT 1308.1 30.725 1310.91 36.765 ;
      RECT 1319.34 30.725 1322.15 36.765 ;
      RECT 1330.58 30.725 1333.39 36.765 ;
      RECT 1341.82 30.725 1344.63 36.765 ;
      RECT 1353.06 30.725 1355.87 36.765 ;
      RECT 1364.3 30.725 1367.11 36.765 ;
      RECT 1375.54 30.725 1378.35 36.765 ;
      RECT 1386.78 30.725 1389.59 36.765 ;
      RECT 1398.02 30.725 1400.83 36.765 ;
      RECT 1409.26 30.725 1412.07 36.765 ;
      RECT 1420.5 30.725 1423.31 36.765 ;
      RECT 1431.74 30.725 1434.55 36.765 ;
      RECT 1442.98 30.725 1445.79 36.765 ;
      RECT 1454.22 30.725 1457.03 36.765 ;
      RECT 1465.46 30.725 1468.27 36.765 ;
      RECT 1476.7 30.725 1479.51 36.765 ;
      RECT 1487.94 30.725 1490.75 36.765 ;
      RECT 1499.18 30.725 1501.99 36.765 ;
      RECT 1510.42 30.725 1513.23 36.765 ;
      RECT 1521.66 30.725 1524.47 36.765 ;
      RECT 1532.9 30.725 1535.71 36.765 ;
      RECT 1544.14 30.725 1546.95 36.765 ;
      RECT 1555.38 30.725 1558.19 36.765 ;
      RECT 1566.62 30.725 1569.43 36.765 ;
      RECT 1577.86 30.725 1580.67 36.765 ;
      RECT 1589.1 30.725 1591.91 36.765 ;
      RECT 1600.34 30.725 1603.15 36.765 ;
      RECT 1611.58 30.725 1614.39 36.765 ;
      RECT 1622.82 30.725 1625.63 36.765 ;
  END
END IHPSG13_SYNTHETIC_ROM_1P_49152x39

END LIBRARY
